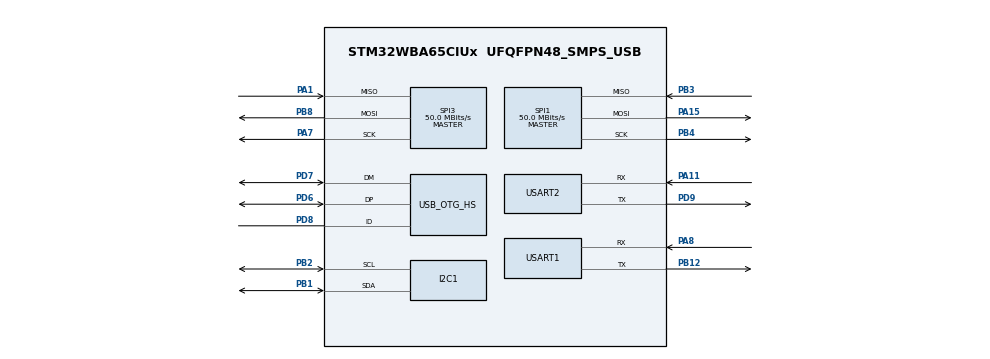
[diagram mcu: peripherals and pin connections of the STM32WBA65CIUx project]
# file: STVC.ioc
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CORTEX_M33_NS.userName=CORTEX_M33
I2C1.Timing=0x10C0ECFF
Mcu.Family=STM32WBA
Mcu.Name=STM32WBA65CIUx
Mcu.Package=UFQFPN48_SMPS_USB
NVIC.PriorityGroup=NVIC_PRIORITYGROUP_4
NVIC.RADIO_IRQn=true\:0\:0\:false\:false\:true\:false\:false\:true
OSC_IN.Mode=HSE-External-Oscillator
OSC_IN.Signal=RCC_OSC_IN
OSC_OUT.Mode=HSE-External-Oscillator
OSC_OUT.Signal=RCC_OSC_OUT
PA1.Mode=Full_Duplex_Master
PA1.Signal=SPI3_MISO
PA11.Mode=Asynchronous
PA11.Signal=USART2_RX
PA15(JTDI).Mode=Full_Duplex_Master
PA15(JTDI).Signal=SPI1_MOSI
PA7.Mode=Full_Duplex_Master
PA7.Signal=SPI3_SCK
PA8.Mode=Asynchronous
PA8.Signal=USART1_RX
PB1.Mode=I2C
PB1.Signal=I2C1_SDA
PB12.Mode=Asynchronous
PB12.Signal=USART1_TX
PB2.Mode=I2C
PB2.Signal=I2C1_SCL
PB3(JTDO/TRACESWO).Mode=Full_Duplex_Master
PB3(JTDO/TRACESWO).Signal=SPI1_MISO
PB4(NJRST).Mode=Full_Duplex_Master
PB4(NJRST).Signal=SPI1_SCK
PB8.Mode=Full_Duplex_Master
PB8.Signal=SPI3_MOSI
PD6.Mode=Dual_Role_Device
PD6.Signal=USB_OTG_HS_DP
PD7.Mode=Dual_Role_Device
PD7.Signal=USB_OTG_HS_DM
PD8.Mode=Dual_Role_Device
PD8.Signal=USB_OTG_HS_ID
PD9.Mode=Asynchronous
PD9.Signal=USART2_TX
ProjectManager.HeapSize=0x200
ProjectManager.StackSize=0x400
ProjectManager.TargetToolchain=STM32CubeIDE
RCC.ADCFreq_Value=100000000
RCC.AHB5CLKDivider=DIV4
RCC.AHBFreq_Value=100000000
RCC.APB1Freq_Value=100000000
RCC.APB1TimFreq_Value=100000000
RCC.APB2Freq_Value=100000000
RCC.APB2TimFreq_Value=100000000
RCC.CortexFreq_Value=12500000
RCC.HCLKFreq_Value=100000000
RCC.HSE_VALUE=32000000
RCC.HSI_VALUE=16000000
RCC.LSE_VALUE=32768
RCC.LSI1_VALUE=32000
RCC.LSI2_VALUE=32000
RCC.PLLFRACN=4096
RCC.PLLM=2
RCC.PLLN=12
RCC.PLLSourceVirtual=RCC_PLLSOURCE_HSE
RCC.SYSCLKFreq_VALUE=100000000
RCC.SYSCLKSourceVirtual=RCC_SYSCLKSOURCE_PLLCLK
RCC.VCOOutputFreq_Value=200000000
SPI1.CalculateBaudRate=50.0 MBits/s
SPI1.Direction=SPI_DIRECTION_2LINES
SPI1.Mode=SPI_MODE_MASTER
SPI1.VirtualType=VM_MASTER
SPI3.CalculateBaudRate=50.0 MBits/s
SPI3.Direction=SPI_DIRECTION_2LINES
SPI3.Mode=SPI_MODE_MASTER
SPI3.VirtualType=VM_MASTER
USART1.VirtualMode-Asynchronous=VM_ASYNC
USART2.VirtualMode-Asynchronous=VM_ASYNC
USB_OTG_HS.VirtualMode=DRD
VP_CORTEX_M33_NS_VS_Hclk.Mode=Hclk_Mode
VP_MEMORYMAP_VS_MEMORYMAP.Mode=CurAppReg
VP_PWR_VS_SECSignals.Mode=Security/Privilege
VP_RF_VS_RF.Mode=RF_Activate
VP_USB_OTG_HS1_USB_OTG_HS_DR.Mode=activate
board=custom

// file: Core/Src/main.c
/* USER CODE BEGIN Header */
/**
  ******************************************************************************
  * @file           : main.c
  * @brief          : Main program body
  ******************************************************************************
  * @attention
  *
  * Copyright (c) 2026 STMicroelectronics.
  * All rights reserved.
  *
  * This software is licensed under terms that can be found in the LICENSE file
  * in the root directory of this software component.
  * If no LICENSE file comes with this software, it is provided AS-IS.
  *
  ******************************************************************************
  */
/* USER CODE END Header */
#include "main.h"

I2C_HandleTypeDef hi2c1;

SPI_HandleTypeDef hspi1;
SPI_HandleTypeDef hspi3;

UART_HandleTypeDef huart1;
UART_HandleTypeDef huart2;

PCD_HandleTypeDef hpcd_USB_OTG_HS;

void SystemClock_Config(void);
static void MX_GPIO_Init(void);
static void MX_I2C1_Init(void);
static void MX_SPI1_Init(void);
static void MX_SPI3_Init(void);
static void MX_USART1_UART_Init(void);
static void MX_USART2_UART_Init(void);

int main(void)
{

  /* MCU Configuration--------------------------------------------------------*/

  /* Reset of all peripherals, Initializes the Flash interface and the Systick. */
  HAL_Init();

  /* Configure the system clock */
  SystemClock_Config();

  /* Initialize all configured peripherals */
  MX_GPIO_Init();
  MX_I2C1_Init();
  MX_SPI1_Init();
  MX_SPI3_Init();
  MX_USART1_UART_Init();
  MX_USART2_UART_Init();
  MX_USB_OTG_HS_PCD_Init();

  /* Infinite loop */
  while (1)
  {

  }
}

void SystemClock_Config(void)
{
  RCC_OscInitTypeDef RCC_OscInitStruct = {0};
  RCC_ClkInitTypeDef RCC_ClkInitStruct = {0};

  /** Supply configuration update enable
  */
  HAL_PWREx_ConfigSupply(PWR_LDO_SUPPLY);

  /** Configure the main internal regulator output voltage
  */
  if (HAL_PWREx_ControlVoltageScaling(PWR_REGULATOR_VOLTAGE_SCALE1) != HAL_OK)
  {
    Error_Handler();
  }

  /** Initializes the CPU, AHB and APB busses clocks
  */
  RCC_OscInitStruct.OscillatorType = RCC_OSCILLATORTYPE_HSE;
  RCC_OscInitStruct.HSEState = RCC_HSE_ON;
  RCC_OscInitStruct.HSEDiv = RCC_HSE_DIV1;
  RCC_OscInitStruct.PLL1.PLLState = RCC_PLL_ON;
  RCC_OscInitStruct.PLL1.PLLSource = RCC_PLLSOURCE_HSE;
  RCC_OscInitStruct.PLL1.PLLM = 2;
  RCC_OscInitStruct.PLL1.PLLN = 12;
  RCC_OscInitStruct.PLL1.PLLP = 2;
  RCC_OscInitStruct.PLL1.PLLQ = 2;
  RCC_OscInitStruct.PLL1.PLLR = 2;
  RCC_OscInitStruct.PLL1.PLLFractional = 4096;
  if (HAL_RCC_OscConfig(&RCC_OscInitStruct) != HAL_OK)
  {
    Error_Handler();
  }

  /** Initializes the CPU, AHB and APB busses clocks
  */
  RCC_ClkInitStruct.ClockType = RCC_CLOCKTYPE_HCLK|RCC_CLOCKTYPE_SYSCLK
                              |RCC_CLOCKTYPE_PCLK1|RCC_CLOCKTYPE_PCLK2
                              |RCC_CLOCKTYPE_PCLK7|RCC_CLOCKTYPE_HCLK5;
  RCC_ClkInitStruct.SYSCLKSource = RCC_SYSCLKSOURCE_PLLCLK;
  RCC_ClkInitStruct.AHBCLKDivider = RCC_SYSCLK_DIV1;
  RCC_ClkInitStruct.APB1CLKDivider = RCC_HCLK_DIV1;
  RCC_ClkInitStruct.APB2CLKDivider = RCC_HCLK_DIV1;
  RCC_ClkInitStruct.APB7CLKDivider = RCC_HCLK_DIV1;
  RCC_ClkInitStruct.AHB5_PLL1_CLKDivider = RCC_SYSCLK_PLL1_DIV4;
  RCC_ClkInitStruct.AHB5_HSEHSI_CLKDivider = RCC_SYSCLK_HSEHSI_DIV1;

  if (HAL_RCC_ClockConfig(&RCC_ClkInitStruct, FLASH_LATENCY_3) != HAL_OK)
  {
    Error_Handler();
  }
}

static void MX_I2C1_Init(void)
{

  hi2c1.Instance = I2C1;
  hi2c1.Init.Timing = 0x10C0ECFF;
  hi2c1.Init.OwnAddress1 = 0;
  hi2c1.Init.AddressingMode = I2C_ADDRESSINGMODE_7BIT;
  hi2c1.Init.DualAddressMode = I2C_DUALADDRESS_DISABLE;
  hi2c1.Init.OwnAddress2 = 0;
  hi2c1.Init.OwnAddress2Masks = I2C_OA2_NOMASK;
  hi2c1.Init.GeneralCallMode = I2C_GENERALCALL_DISABLE;
  hi2c1.Init.NoStretchMode = I2C_NOSTRETCH_DISABLE;
  if (HAL_I2C_Init(&hi2c1) != HAL_OK)
  {
    Error_Handler();
  }

  /** Configure Analogue filter
  */
  if (HAL_I2CEx_ConfigAnalogFilter(&hi2c1, I2C_ANALOGFILTER_ENABLE) != HAL_OK)
  {
    Error_Handler();
  }

  /** Configure Digital filter
  */
  if (HAL_I2CEx_ConfigDigitalFilter(&hi2c1, 0) != HAL_OK)
  {
    Error_Handler();
  }

}

static void MX_SPI1_Init(void)
{

  SPI_AutonomousModeConfTypeDef HAL_SPI_AutonomousMode_Cfg_Struct = {0};

  /* SPI1 parameter configuration*/
  hspi1.Instance = SPI1;
  hspi1.Init.Mode = SPI_MODE_MASTER;
  hspi1.Init.Direction = SPI_DIRECTION_2LINES;
  hspi1.Init.DataSize = SPI_DATASIZE_4BIT;
  hspi1.Init.CLKPolarity = SPI_POLARITY_LOW;
  hspi1.Init.CLKPhase = SPI_PHASE_1EDGE;
  hspi1.Init.NSS = SPI_NSS_SOFT;
  hspi1.Init.BaudRatePrescaler = SPI_BAUDRATEPRESCALER_2;
  hspi1.Init.FirstBit = SPI_FIRSTBIT_MSB;
  hspi1.Init.TIMode = SPI_TIMODE_DISABLE;
  hspi1.Init.CRCCalculation = SPI_CRCCALCULATION_DISABLE;
  hspi1.Init.CRCPolynomial = 0x7;
  hspi1.Init.NSSPMode = SPI_NSS_PULSE_ENABLE;
  hspi1.Init.NSSPolarity = SPI_NSS_POLARITY_LOW;
  hspi1.Init.FifoThreshold = SPI_FIFO_THRESHOLD_01DATA;
  hspi1.Init.MasterSSIdleness = SPI_MASTER_SS_IDLENESS_00CYCLE;
  hspi1.Init.MasterInterDataIdleness = SPI_MASTER_INTERDATA_IDLENESS_00CYCLE;
  hspi1.Init.MasterReceiverAutoSusp = SPI_MASTER_RX_AUTOSUSP_DISABLE;
  hspi1.Init.MasterKeepIOState = SPI_MASTER_KEEP_IO_STATE_DISABLE;
  hspi1.Init.IOSwap = SPI_IO_SWAP_DISABLE;
  hspi1.Init.ReadyMasterManagement = SPI_RDY_MASTER_MANAGEMENT_INTERNALLY;
  hspi1.Init.ReadyPolarity = SPI_RDY_POLARITY_HIGH;
  if (HAL_SPI_Init(&hspi1) != HAL_OK)
  {
    Error_Handler();
  }
  HAL_SPI_AutonomousMode_Cfg_Struct.TriggerState = SPI_AUTO_MODE_DISABLE;
  if (HAL_SPIEx_SetConfigAutonomousMode(&hspi1, &HAL_SPI_AutonomousMode_Cfg_Struct) != HAL_OK)
  {
    Error_Handler();
  }

}

static void MX_SPI3_Init(void)
{

  SPI_AutonomousModeConfTypeDef HAL_SPI_AutonomousMode_Cfg_Struct = {0};

  /* SPI3 parameter configuration*/
  hspi3.Instance = SPI3;
  hspi3.Init.Mode = SPI_MODE_MASTER;
  hspi3.Init.Direction = SPI_DIRECTION_2LINES;
  hspi3.Init.DataSize = SPI_DATASIZE_8BIT;
  hspi3.Init.CLKPolarity = SPI_POLARITY_LOW;
  hspi3.Init.CLKPhase = SPI_PHASE_1EDGE;
  hspi3.Init.NSS = SPI_NSS_SOFT;
  hspi3.Init.BaudRatePrescaler = SPI_BAUDRATEPRESCALER_2;
  hspi3.Init.FirstBit = SPI_FIRSTBIT_MSB;
  hspi3.Init.TIMode = SPI_TIMODE_DISABLE;
  hspi3.Init.CRCCalculation = SPI_CRCCALCULATION_DISABLE;
  hspi3.Init.CRCPolynomial = 0x7;
  hspi3.Init.NSSPMode = SPI_NSS_PULSE_ENABLE;
  hspi3.Init.NSSPolarity = SPI_NSS_POLARITY_LOW;
  hspi3.Init.FifoThreshold = SPI_FIFO_THRESHOLD_01DATA;
  hspi3.Init.MasterSSIdleness = SPI_MASTER_SS_IDLENESS_00CYCLE;
  hspi3.Init.MasterInterDataIdleness = SPI_MASTER_INTERDATA_IDLENESS_00CYCLE;
  hspi3.Init.MasterReceiverAutoSusp = SPI_MASTER_RX_AUTOSUSP_DISABLE;
  hspi3.Init.MasterKeepIOState = SPI_MASTER_KEEP_IO_STATE_DISABLE;
  hspi3.Init.IOSwap = SPI_IO_SWAP_DISABLE;
  hspi3.Init.ReadyMasterManagement = SPI_RDY_MASTER_MANAGEMENT_INTERNALLY;
  hspi3.Init.ReadyPolarity = SPI_RDY_POLARITY_HIGH;
  if (HAL_SPI_Init(&hspi3) != HAL_OK)
  {
    Error_Handler();
  }
  HAL_SPI_AutonomousMode_Cfg_Struct.TriggerState = SPI_AUTO_MODE_DISABLE;
  if (HAL_SPIEx_SetConfigAutonomousMode(&hspi3, &HAL_SPI_AutonomousMode_Cfg_Struct) != HAL_OK)
  {
    Error_Handler();
  }

}

static void MX_USART1_UART_Init(void)
{

  huart1.Instance = USART1;
  huart1.Init.BaudRate = 115200;
  huart1.Init.WordLength = UART_WORDLENGTH_8B;
  huart1.Init.StopBits = UART_STOPBITS_1;
  huart1.Init.Parity = UART_PARITY_NONE;
  huart1.Init.Mode = UART_MODE_TX_RX;
  huart1.Init.HwFlowCtl = UART_HWCONTROL_NONE;
  huart1.Init.OverSampling = UART_OVERSAMPLING_16;
  huart1.Init.OneBitSampling = UART_ONE_BIT_SAMPLE_DISABLE;
  huart1.Init.ClockPrescaler = UART_PRESCALER_DIV1;
  huart1.AdvancedInit.AdvFeatureInit = UART_ADVFEATURE_NO_INIT;
  if (HAL_UART_Init(&huart1) != HAL_OK)
  {
    Error_Handler();
  }
  if (HAL_UARTEx_SetTxFifoThreshold(&huart1, UART_TXFIFO_THRESHOLD_1_8) != HAL_OK)
  {
    Error_Handler();
  }
  if (HAL_UARTEx_SetRxFifoThreshold(&huart1, UART_RXFIFO_THRESHOLD_1_8) != HAL_OK)
  {
    Error_Handler();
  }
  if (HAL_UARTEx_DisableFifoMode(&huart1) != HAL_OK)
  {
    Error_Handler();
  }

}

static void MX_USART2_UART_Init(void)
{

  huart2.Instance = USART2;
  huart2.Init.BaudRate = 115200;
  huart2.Init.WordLength = UART_WORDLENGTH_8B;
  huart2.Init.StopBits = UART_STOPBITS_1;
  huart2.Init.Parity = UART_PARITY_NONE;
  huart2.Init.Mode = UART_MODE_TX_RX;
  huart2.Init.HwFlowCtl = UART_HWCONTROL_NONE;
  huart2.Init.OverSampling = UART_OVERSAMPLING_16;
  huart2.Init.OneBitSampling = UART_ONE_BIT_SAMPLE_DISABLE;
  huart2.Init.ClockPrescaler = UART_PRESCALER_DIV1;
  huart2.AdvancedInit.AdvFeatureInit = UART_ADVFEATURE_NO_INIT;
  if (HAL_UART_Init(&huart2) != HAL_OK)
  {
    Error_Handler();
  }
  if (HAL_UARTEx_SetTxFifoThreshold(&huart2, UART_TXFIFO_THRESHOLD_1_8) != HAL_OK)
  {
    Error_Handler();
  }
  if (HAL_UARTEx_SetRxFifoThreshold(&huart2, UART_RXFIFO_THRESHOLD_1_8) != HAL_OK)
  {
    Error_Handler();
  }
  if (HAL_UARTEx_DisableFifoMode(&huart2) != HAL_OK)
  {
    Error_Handler();
  }

}

void MX_USB_OTG_HS_PCD_Init(void)
{

  hpcd_USB_OTG_HS.Instance = USB_OTG_HS;
  hpcd_USB_OTG_HS.Init.dev_endpoints = 9;
  hpcd_USB_OTG_HS.Init.speed = PCD_SPEED_HIGH;
  hpcd_USB_OTG_HS.Init.phy_itface = USB_OTG_HS_EMBEDDED_PHY;
  hpcd_USB_OTG_HS.Init.Sof_enable = DISABLE;
  hpcd_USB_OTG_HS.Init.low_power_enable = DISABLE;
  hpcd_USB_OTG_HS.Init.use_dedicated_ep1 = DISABLE;
  hpcd_USB_OTG_HS.Init.vbus_sensing_enable = DISABLE;
  hpcd_USB_OTG_HS.Init.dma_enable = DISABLE;
  if (HAL_PCD_Init(&hpcd_USB_OTG_HS) != HAL_OK)
  {
    Error_Handler();
  }

}

static void MX_GPIO_Init(void)
{

  /* GPIO Ports Clock Enable */
  __HAL_RCC_GPIOB_CLK_ENABLE();
  __HAL_RCC_GPIOA_CLK_ENABLE();
  __HAL_RCC_GPIOD_CLK_ENABLE();

}

void Error_Handler(void)
{
  __disable_irq();
  while (1)
  {
  }
}
